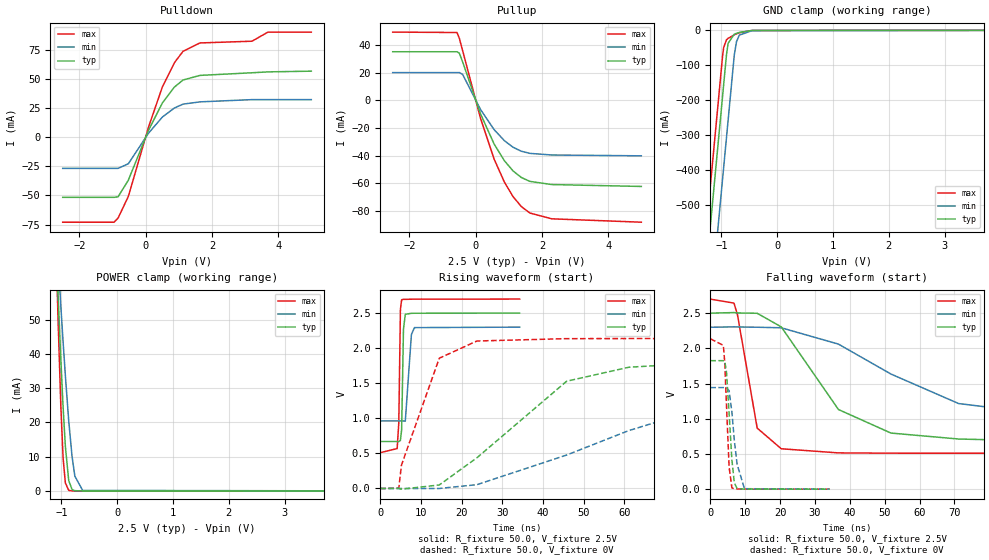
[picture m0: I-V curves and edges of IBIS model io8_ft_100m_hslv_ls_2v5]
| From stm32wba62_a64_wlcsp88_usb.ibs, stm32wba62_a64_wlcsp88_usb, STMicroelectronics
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[Model]   io8_ft_100m_hslv_ls_2v5
Model_type I/O
Polarity   Non-Inverting
Enable   Active-Low
| CAP_THRESHOLD on pad IOFT is "UDTCAPC" :
| Rising=30.0% of vddiom   Falling=70.0% of vddiom
| C_comp min and max val. don't necessarily correlate with the min and max pvt
| but are the smallest and greatest pad capacitance found.
| var   typ   min   max
C_comp   3.76303pF  3.70258pF  3.86851pF
|C_comp_pullup   2.23764pF  2.13239pF  2.37539pF
|C_comp_pulldown   1.52539pF  1.57019pF  1.49312pF
Vinl = 1.15V
Vinh = 1.35V
Vmeas = 1.25V   | Reference voltage for timing measurements
Cref  = 50.0pF   | Timing specification test load capacitance value
Rref  = 1.0MOhm   | Timing specification test load resistance value
Vref  = 1.375V   | Timing specification test load voltage
[Model Spec]
| TIME_THRESHOLD on pin ZIV11 is "CMOS" :
| Rising=50.0% of vdd   Falling=50.0% of vdd
Vinl 992.50000mV 921.50000mV 1.05850V
Vinh 1.43350V 1.32250V 1.51250V
| variable   typ   min   max
[Temperature Range] 25.0 140.0 -40.0
| variable   typ   min   max
[Voltage Range] 2.5V 2.3V 2.7V
| variable   typ   min   max
[POWER Clamp Reference] 2.5V 2.3V 2.7V
| variable   typ   min   max
[GND Clamp Reference] 0V 0V 0V
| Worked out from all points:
|   slope of the pulldown table from 0 to 0.375 V, typ, clamps not added: 16.2 ohm
|   slope of the pullup table from 0 to 0.375 V, typ, clamps not added: 16.7 ohm
|   GND clamp passes 1 mA (typ) near -0.51 V on its own axis
|   POWER clamp passes 1 mA (typ) near -0.83 V on its own axis
|   rising waveform, R_fixture 50.0, V_fixture 2.5V: 20-80 % time 285ps typ, 437ps min, 287ps max; typ from 0.67 V to 2.5 V
|   falling waveform, R_fixture 50.0, V_fixture 2.5V: 20-80 % time 15.8ns typ, 32.2ns min, 4.57ns max; typ from 2.5 V to 0.67 V
|   rising waveform, R_fixture 50.0, V_fixture 0V: 20-80 % time 21.6ns typ, 41.7ns min, 6.82ns max; typ from 0 V to 1.82 V
|   falling waveform, R_fixture 50.0, V_fixture 0V: 20-80 % time 1.29ns typ, 1.85ns min, 1.03ns max; typ from 1.82 V to 0 V
[POWER Clamp]
-2.5V     733.7mA    502.6mA    1.062A
-1.09V    69.42mA    75.17mA    67.14mA
-1.08V    65.31mA    72.42mA    61.23mA
-1.06V    57.23mA    66.98mA    49.77mA
-1.01V    38.06mA    53.68mA    24.29mA
-970mV    24.36mA    43.46mA    9.575mA
-930mV    13.06mA    33.74mA    2.352mA
-870mV    3.065mA    20.56mA    165.9uA
-810mV    418.4uA    10.06mA    10.3uA
-760mV    69.41uA    4.321mA    1.008uA
-620mV    424.8nA    151.9uA    1.655nA
5V        0A         0A         0A
[GND Clamp]
-2.5V     -2.774A    -3.011A    -2.658A
-1.45V    -988.6mA   -1.226A    -873.4mA
-1.21V    -580.6mA   -818.3mA   -465.4mA
-980mV    -189.6mA   -427.3mA   -74.41mA
-960mV    -155.6mA   -393.3mA   -49.14mA
-910mV    -70.61mA   -308.3mA   -27.43mA
-880mV    -37.05mA   -257.3mA   -22.95mA
-770mV    -11.2mA    -71.03mA   -13.02mA
-730mV    -8.651mA   -32.36mA   -10.11mA
-680mV    -6.129mA   -13.76mA   -6.945mA
-450mV    -356.3uA   -840.3uA   -213.1uA
5V        1.758nA    357.7nA    738.1pA
| variable   typ   min   max
[Pullup Reference] 2.5V 2.3V 2.7V
| variable   typ   min   max
[Pulldown Reference] 0V 0V 0V
[Pullup]
-2.5V     35.35mA    20.25mA    49.61mA
-560mV    35.35mA    20.25mA    49.3mA
-490mV    34.29mA    20.25mA    45.08mA
-390mV    27.95mA    18.88mA    36.11mA
150mV     -9.726mA   -6.535mA   -13.02mA
560mV     -31.59mA   -21.16mA   -42.52mA
870mV     -43.7mA    -29.15mA   -59.21mA
1.13V     -51.06mA   -33.88mA   -69.7mA
1.38V     -55.84mA   -36.8mA    -76.9mA
1.64V     -58.66mA   -38.35mA   -81.62mA
2.3V      -60.96mA   -39.52mA   -85.81mA
5V        -62.33mA   -40.13mA   -88.25mA
[Pulldown]
-2.5V     -51.61mA   -26.66mA   -73.01mA
-950mV    -51.61mA   -26.66mA   -73.01mA
-830mV    -51.13mA   -26.66mA   -69.5mA
-520mV    -36.86mA   -22.67mA   -50.81mA
90mV      6.214mA    3.696mA    8.997mA
510mV     29.86mA    17.62mA    43.74mA
870mV     43.36mA    25.34mA    64.34mA
1.13V     49.44mA    28.66mA    74.15mA
1.64V     53.42mA    30.62mA    81.36mA
3.21V     55.67mA    32.54mA    82.85mA
3.69V     56.44mA    32.54mA    90.68mA
5V        57.06mA    32.54mA    90.71mA
[Ramp]
dV/dt_r 1.09518V/21.22471ns 865.48725mV/41.50367ns 1.28201V/6.70344ns
dV/dt_f 1.09819V/15.37327ns 801.46434mV/31.97693ns 1.31366V/4.4126ns
R_load = 50.0
| Removed startup time: 0s 0s 0s  .
| Removed end time: 34.25ns.
[Rising Waveform]
R_fixture   = 50.0
V_fixture   = 2.5V
V_fixture_min = 2.3V
V_fixture_max = 2.7V
0s        669.7mV    963mV      510.6mV
4.15ns    669.7mV    963mV      569.2mV
4.55ns    668.8mV    963mV      935.7mV
4.95ns    684.4mV    963mV      2.551V
5.25ns    840mV      963mV      2.69V
5.7ns     2.273V     962.6mV    2.696V
6.15ns    2.483V     960.2mV    2.696V
7.65ns    2.497V     2.195V     2.698V
8.4ns     2.498V     2.293V     2.699V
34.25ns   2.5V       2.3V       2.7V
| Removed startup time: 0s 0s 0s  .
| Removed end time: 249.2ns.
[Falling Waveform]
R_fixture   = 50.0
V_fixture   = 2.5V
V_fixture_min = 2.3V
V_fixture_max = 2.7V
0s        2.5V       2.3V       2.7V
6.8ns     2.508V     2.305V     2.642V
7.8ns     2.503V     2.304V     2.476V
13.45ns   2.498V     2.3V       867.3mV
20.35ns   2.305V     2.292V     573.9mV
36.75ns   1.131V     2.06V      515.2mV
51.8ns    796.8mV    1.635V     511.1mV
71.2ns    712.3mV    1.216V     510.6mV
96.65ns   682.3mV    1.062V     510.6mV
249.2ns   669.7mV    964.2mV    510.6mV
| Removed startup time: 0s 0s 0s  .
| Removed end time: 249.25ns.
[Rising Waveform]
R_fixture   = 50.0
V_fixture   = 0V
V_fixture_min = 0V
V_fixture_max = 0V
0s        5.305nV    128.7nV    4.787nV
4.55ns    230.3uV    1.988uV    5.187mV
5.2ns     -9.662mV   14.49uV    332mV
14.5ns    50.22mV    348.4uV    1.857V
23.75ns   437.9mV    54.54mV    2.102V
45.8ns    1.529V     477mV      2.136V
61.05ns   1.728V     825.2mV    2.137V
81.4ns    1.797V     1.186V     2.137V
107.8ns   1.819V     1.355V     2.137V
249.3ns   1.825V     1.442V     2.137V
| Removed startup time: 0s 0s 0s  .
| Removed end time: 34.2ns.
[Falling Waveform]
R_fixture   = 50.0
V_fixture   = 0V
V_fixture_min = 0V
V_fixture_max = 0V
0s        1.825V     1.443V     2.137V
3.75ns    1.825V     1.443V     2.042V
4.15ns    1.819V     1.443V     1.8V
4.65ns    1.662V     1.443V     1.183V
5.4ns     1.072V     1.397V     313.7mV
6.2ns     414mV      1.094V     19.02mV
6.9ns     89.08mV    691.3mV    4.599mV
7.7ns     7.654mV    352.7mV    2.44mV
9.8ns     1.416mV    6.88mV     1.424mV
34.2ns    184.7uV    284.3uV    118.1uV
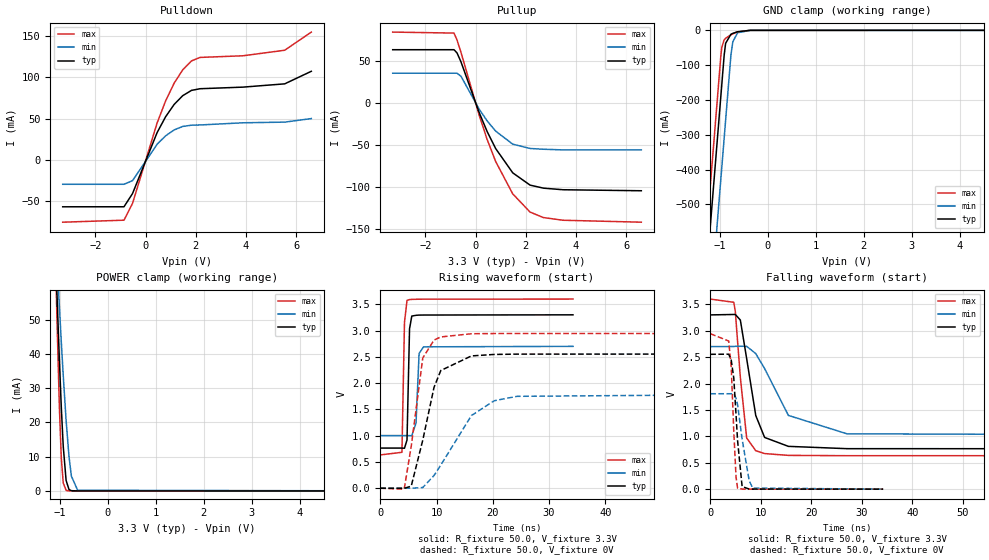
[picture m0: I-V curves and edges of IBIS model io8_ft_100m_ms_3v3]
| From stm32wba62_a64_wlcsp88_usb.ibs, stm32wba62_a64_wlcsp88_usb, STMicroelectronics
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[Model]   io8_ft_100m_ms_3v3
Model_type I/O
Polarity   Non-Inverting
Enable   Active-Low
| CAP_THRESHOLD on pad IOFT is "UDTCAPC" :
| Rising=30.0% of vddiom   Falling=70.0% of vddiom
| C_comp min and max val. don't necessarily correlate with the min and max pvt
| but are the smallest and greatest pad capacitance found.
| var   typ   min   max
C_comp   3.79769pF  3.69235pF  3.85115pF
|C_comp_pullup   2.35213pF  2.17427pF  2.43332pF
|C_comp_pulldown   1.44556pF  1.51808pF  1.41784pF
Vinl = 1.35V
Vinh = 1.8V
Vmeas = 1.65V   | Reference voltage for timing measurements
Cref  = 50.0pF   | Timing specification test load capacitance value
Rref  = 1.0MOhm   | Timing specification test load resistance value
Vref  = 1.815V   | Timing specification test load voltage
[Model Spec]
| TIME_THRESHOLD on pin ZIV11 is "CMOS" :
| Rising=50.0% of vdd   Falling=50.0% of vdd
Vinl 1.29050V 1.08050V 1.37650V
Vinh 1.79850V 1.52050V 1.90250V
| variable   typ   min   max
[Temperature Range] 25.0 140.0 -40.0
| variable   typ   min   max
[Voltage Range] 3.3V 2.7V 3.6V
| variable   typ   min   max
[POWER Clamp Reference] 3.3V 2.7V 3.6V
| variable   typ   min   max
[GND Clamp Reference] 0V 0V 0V
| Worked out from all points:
|   slope of the pulldown table from 0 to 0.495 V, typ, clamps not added: 14 ohm
|   slope of the pullup table from 0 to 0.495 V, typ, clamps not added: 13.8 ohm
|   GND clamp passes 1 mA (typ) near -0.51 V on its own axis
|   POWER clamp passes 1 mA (typ) near -0.83 V on its own axis
|   rising waveform, R_fixture 50.0, V_fixture 3.3V: 20-80 % time 257ps typ, 344ps min, 242ps max; typ from 0.764 V to 3.3 V
|   falling waveform, R_fixture 50.0, V_fixture 3.3V: 20-80 % time 2.84ns typ, 6.11ns min, 1.62ns max; typ from 3.3 V to 0.764 V
|   rising waveform, R_fixture 50.0, V_fixture 0V: 20-80 % time 3.16ns typ, 6.58ns min, 2.08ns max; typ from 0 V to 2.55 V
|   falling waveform, R_fixture 50.0, V_fixture 0V: 20-80 % time 1.01ns typ, 1.58ns min, 770ps max; typ from 2.55 V to 0 V
[POWER Clamp]
-3.3V     1.123A     753mA      1.645A
-1.09V    69.42mA    75.17mA    67.14mA
-1.08V    65.31mA    72.42mA    61.23mA
-1.06V    57.23mA    66.98mA    49.77mA
-1.01V    38.06mA    53.68mA    24.29mA
-970mV    24.36mA    43.46mA    9.575mA
-930mV    13.06mA    33.74mA    2.352mA
-870mV    3.065mA    20.56mA    165.9uA
-810mV    418.4uA    10.06mA    10.3uA
-760mV    69.41uA    4.321mA    1.009uA
-630mV    611.5nA    197uA      2.727nA
6.6V      0A         0A         0A
[GND Clamp]
-3.3V     -4.134A    -4.372A    -4.018A
-1.59V    -1.227A    -1.465A    -1.111A
-1.25V    -648.9mA   -886.9mA   -533mA
-980mV    -189.9mA   -427.9mA   -74mA
-960mV    -155.9mA   -393.9mA   -48.8mA
-910mV    -70.86mA   -308.9mA   -27.2mA
-880mV    -37.23mA   -257.9mA   -22.76mA
-770mV    -11.28mA   -71.59mA   -12.95mA
-730mV    -8.709mA   -32.74mA   -10.07mA
-630mV    -4.122mA   -6.943mA   -4.354mA
-370mV    -42.68uA   -212.2uA   -13.03uA
6.6V      2.311nA    506.4nA    1.057nA
| variable   typ   min   max
[Pullup Reference] 3.3V 2.7V 3.6V
| variable   typ   min   max
[Pulldown Reference] 0V 0V 0V
[Pullup]
-3.3V     63.23mA    35.34mA    84.14mA
-860mV    63.23mA    35.34mA    82.96mA
-740mV    59.49mA    35.34mA    74.87mA
-580mV    48.71mA    31.68mA    59.96mA
140mV     -11.11mA   -7.067mA   -14.16mA
460mV     -33.83mA   -21.24mA   -43.26mA
800mV     -54.04mA   -33.36mA   -69.41mA
1.48V     -82.86mA   -48.82mA   -107.8mA
2.17V     -97.42mA   -53.93mA   -129.4mA
2.7V      -101mA     -54.85mA   -135.9mA
3.48V     -102.9mA   -55.62mA   -139.1mA
6.6V      -104.1mA   -55.62mA   -141.4mA
[Pulldown]
-3.3V     -56.7mA    -29.42mA   -75.36mA
-860mV    -56.67mA   -29.42mA   -72.94mA
-520mV    -40.69mA   -25.01mA   -52.64mA
460mV     33.25mA    19.09mA    44.92mA
800mV     52.54mA    29.36mA    71.75mA
1.14V     67.41mA    36.49mA    93.2mA
1.48V     77.97mA    40.67mA    109.3mA
1.83V     84.38mA    42.18mA    120.1mA
2.17V     86.37mA    42.45mA    124.3mA
3.88V     88.31mA    45.1mA     126.3mA
5.54V     92.28mA    45.89mA    133mA
6.6V      107.5mA    50.2mA     155mA
[Ramp]
dV/dt_r 1.53258V/3.14502ns 1.08444V/6.42433ns 1.76673V/2.08391ns
dV/dt_f 1.52157V/2.56919ns 1.019V/5.67962ns 1.77971V/1.61656ns
R_load = 50.0
| Removed startup time: 0s 0s 0s  .
| Removed end time: 34.25ns.
[Rising Waveform]
R_fixture   = 50.0
V_fixture   = 3.3V
V_fixture_min = 2.7V
V_fixture_max = 3.6V
0s        764mV      1.002V     633.8mV
3.85ns    764.1mV    1.002V     683.7mV
4.3ns     761.2mV    1.002V     3.153V
4.75ns    917.8mV    1.002V     3.575V
5.2ns     3.033V     1.001V     3.59V
5.6ns     3.276V     999mV      3.594V
6.35ns    3.291V     1.237V     3.596V
6.9ns     3.295V     2.565V     3.597V
7.7ns     3.296V     2.691V     3.598V
34.25ns   3.3V       2.7V       3.6V
| Removed startup time: 0s 0s 0s  .
| Removed end time: 189.25ns.
[Falling Waveform]
R_fixture   = 50.0
V_fixture   = 3.3V
V_fixture_min = 2.7V
V_fixture_max = 3.6V
0s        3.3V       2.7V       3.6V
4.65ns    3.308V     2.701V     3.539V
4.95ns    3.308V     2.705V     3.365V
5.95ns    3.203V     2.706V     2.115V
7.2ns     2.471V     2.705V     969.3mV
9ns       1.394V     2.567V     727.8mV
10.75ns   979.4mV    2.284V     673.9mV
15.45ns   810.7mV    1.397V     639.7mV
27.05ns   766.9mV    1.048V     634mV
189.3ns   764mV      1.002V     633.8mV
| Removed startup time: 0s 0s 0s  .
| Removed end time: 99.2ns.
[Rising Waveform]
R_fixture   = 50.0
V_fixture   = 0V
V_fixture_min = 0V
V_fixture_max = 0V
0s        20.8nV     123.7nV    58.33nV
4.25ns    -1.312mV   3.786uV    -17.81mV
5.5ns     39.25mV    -134.8uV   797.2mV
7.55ns    914.9mV    13.42mV    2.478V
9.55ns    1.919V     241.9mV    2.82V
10.75ns   2.24V      440.3mV    2.879V
16.2ns    2.518V     1.384V     2.94V
20.25ns   2.546V     1.665V     2.944V
24.3ns    2.552V     1.749V     2.944V
99.2ns    2.554V     1.807V     2.945V
| Removed startup time: 0s 0s 0s  .
| Removed end time: 34.2ns.
[Falling Waveform]
R_fixture   = 50.0
V_fixture   = 0V
V_fixture_min = 0V
V_fixture_max = 0V
0s        2.554V     1.807V     2.945V
3.65ns    2.556V     1.807V     2.805V
4.15ns    2.442V     1.807V     2.307V
4.65ns    2.105V     1.812V     1.089V
5.1ns     1.404V     1.719V     227.3mV
5.4ns     918.9mV    1.602V     19.53mV
6.3ns     49.32mV    947mV      2.27mV
7.7ns     2.286mV    156.8mV    1.162mV
8.4ns     1.629mV    20.95mV    949.3uV
34.2ns    5.948uV    58.14uV    862.4nV
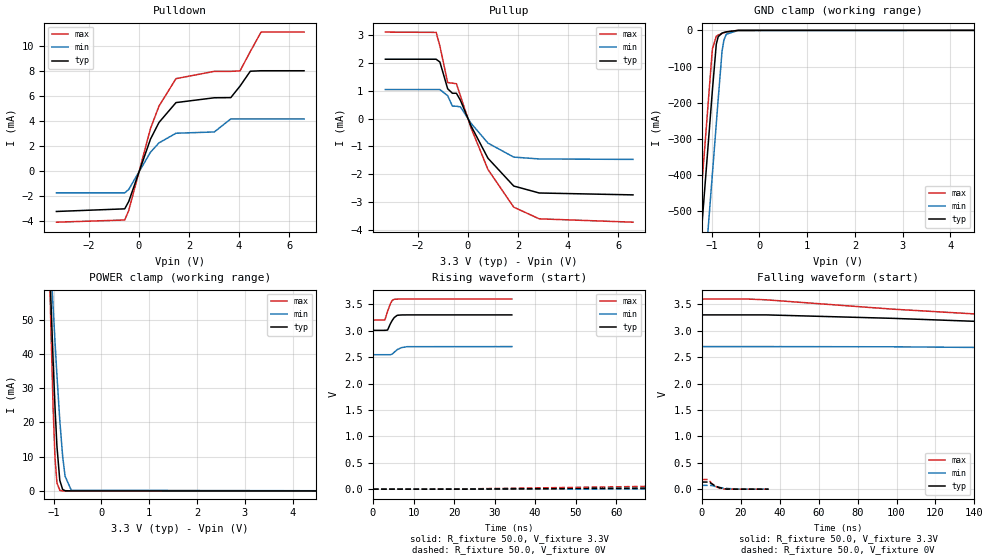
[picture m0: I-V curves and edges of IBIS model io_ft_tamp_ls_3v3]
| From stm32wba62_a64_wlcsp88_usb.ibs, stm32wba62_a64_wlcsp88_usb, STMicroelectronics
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[Model]   io_ft_tamp_ls_3v3
Model_type I/O
Polarity   Non-Inverting
Enable   Active-Low
| CAP_THRESHOLD on pad IOFT is "UDTCAPC" :
| Rising=30.0% of vddios   Falling=70.0% of vddios
| C_comp min and max val. don't necessarily correlate with the min and max pvt
| but are the smallest and greatest pad capacitance found.
| var   typ   min   max
C_comp   2.94466pF  2.88473pF  2.97349pF
|C_comp_pullup   1.80042pF  1.68790pF  1.84110pF
|C_comp_pulldown   1.14423pF  1.19683pF  1.13239pF
Vinl = 1.35V
Vinh = 1.8V
Vmeas = 1.65V   | Reference voltage for timing measurements
Cref  = 50.0pF   | Timing specification test load capacitance value
Rref  = 1.0MOhm   | Timing specification test load resistance value
Vref  = 1.815V   | Timing specification test load voltage
[Model Spec]
| TIME_THRESHOLD on pin ZIV11 is "CMOS" :
| Rising=50.0% of vdd   Falling=50.0% of vdd
Vinl 1.29050V 1.08050V 1.37650V
Vinh 1.79850V 1.52050V 1.90250V
| variable   typ   min   max
[Temperature Range] 25.0 140.0 -40.0
| variable   typ   min   max
[Voltage Range] 3.3V 2.7V 3.6V
| variable   typ   min   max
[POWER Clamp Reference] 3.3V 2.7V 3.6V
| variable   typ   min   max
[GND Clamp Reference] 0V 0V 0V
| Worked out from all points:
|   slope of the pulldown table from 0 to 0.495 V, typ, clamps not added: 186 ohm
|   slope of the pullup table from 0 to 0.495 V, typ, clamps not added: 523 ohm
|   GND clamp passes 1 mA (typ) near -0.54 V on its own axis
|   POWER clamp passes 1 mA (typ) near -0.83 V on its own axis
|   rising waveform, R_fixture 50.0, V_fixture 3.3V: 20-80 % time 1.21ns typ, 1.65ns min, 1.06ns max; typ from 3.01 V to 3.3 V
|   falling waveform, R_fixture 50.0, V_fixture 3.3V: 20-80 % time 142ns typ, 234ns min, 99.7ns max; typ from 3.3 V to 3.01 V
|   rising waveform, R_fixture 50.0, V_fixture 0V: 20-80 % time 166ns typ, 308ns min, 115ns max; typ from 0 V to 0.135 V
|   falling waveform, R_fixture 50.0, V_fixture 0V: 20-80 % time 4.46ns typ, 6.53ns min, 3.74ns max; typ from 0.135 V to 0 V
[POWER Clamp]
-3.3V     1.123A     753mA      1.645A
-1.09V    69.42mA    75.17mA    67.14mA
-1.08V    65.31mA    72.42mA    61.23mA
-1.06V    57.23mA    66.98mA    49.77mA
-1.01V    38.06mA    53.68mA    24.29mA
-970mV    24.36mA    43.46mA    9.575mA
-930mV    13.06mA    33.74mA    2.352mA
-870mV    3.065mA    20.56mA    165.9uA
-810mV    418.4uA    10.06mA    10.3uA
-760mV    69.41uA    4.321mA    1.008uA
-630mV    611nA      197uA      2.689nA
6.6V      0A         0A         0A
[GND Clamp]
-3.3V     -4.108A    -4.338A    -3.993A
-1.47V    -996.5mA   -1.227A    -882.1mA
-1.25V    -622.5mA   -853.4mA   -508.1mA
-990mV    -180.5mA   -411.4mA   -66.09mA
-980mV    -163.5mA   -394.4mA   -51.42mA
-900mV    -38.37mA   -258.4mA   -16.28mA
-860mV    -17.66mA   -190.4mA   -13.03mA
-780mV    -7.657mA   -58.45mA   -8.63mA
-740mV    -5.866mA   -26.35mA   -6.764mA
-690mV    -4.176mA   -10.78mA   -4.712mA
-450mV    -220.4uA   -529.3uA   -129.7uA
6.6V      1.984nA    498.7nA    735.2pA
| variable   typ   min   max
[Pullup Reference] 3.3V 2.7V 3.6V
| variable   typ   min   max
[Pulldown Reference] 0V 0V 0V
[Pullup]
-3.3V     2.139mA    1.048mA    3.116mA
-1.27V    2.139mA    1.048mA    3.106mA
-1.12V    2.038mA    1.048mA    2.612mA
-810mV    1.076mA    826.2uA    1.296mA
-620mV    914.6uA    451.9uA    1.28mA
-460mV    914.6uA    447.1uA    1.257mA
-300mV    660.2uA    425.1uA    820.6uA
120mV     -251.9uA   -160.4uA   -321uA
800mV     -1.423mA   -878.7uA   -1.828mA
1.83V     -2.424mA   -1.383mA   -3.184mA
2.85V     -2.675mA   -1.45mA    -3.605mA
6.6V      -2.743mA   -1.466mA   -3.726mA
[Pulldown]
-3.3V     -3.274mA   -1.782mA   -4.133mA
-570mV    -3.064mA   -1.782mA   -3.957mA
-410mV    -2.48mA    -1.511mA   -3.207mA
460mV     2.522mA    1.473mA    3.369mA
800mV     3.858mA    2.222mA    5.168mA
1.48V     5.45mA     2.995mA    7.37mA
3.01V     5.836mA    3.097mA    7.954mA
3.67V     5.848mA    4.142mA    7.954mA
4.04V     6.772mA    4.142mA    7.991mA
4.45V     7.963mA    4.142mA    9.539mA
4.88V     8.002mA    4.142mA    11.1mA
6.6V      8.002mA    4.142mA    11.1mA
[Ramp]
dV/dt_r 80.89923mV/165.45031ns 43.20406mV/308.11062ns 109.86367mV/114.45653ns
dV/dt_f 175.10448mV/141.49612ns 92.27507mV/233.79531ns 238.66494mV/99.51803ns
R_load = 50.0
| Removed startup time: 0s 0s 0s  .
| Removed end time: 34.25ns.
[Rising Waveform]
R_fixture   = 50.0
V_fixture   = 3.3V
V_fixture_min = 2.7V
V_fixture_max = 3.6V
0s        3.008V     2.546V     3.202V
2.95ns    3.008V     2.546V     3.205V
3.6ns     3.013V     2.546V     3.368V
4.3ns     3.134V     2.546V     3.512V
4.75ns    3.196V     2.558V     3.575V
5.25ns    3.251V     2.594V     3.596V
6ns       3.293V     2.643V     3.599V
7ns       3.299V     2.68V      3.6V
8.4ns     3.3V       2.698V     3.6V
34.25ns   3.3V       2.7V       3.6V
| Removed startup time: 0s 0s 0s  .
| Removed end time: 1.19925us.
[Falling Waveform]
R_fixture   = 50.0
V_fixture   = 3.3V
V_fixture_min = 2.7V
V_fixture_max = 3.6V
0s        3.3V       2.7V       3.6V
23.7ns    3.3V       2.7V       3.6V
33.3ns    3.3V       2.7V       3.585V
97.95ns   3.235V     2.696V     3.409V
158.6ns   3.154V     2.679V     3.279V
195.8ns   3.105V     2.666V     3.238V
244.8ns   3.059V     2.646V     3.216V
342.8ns   3.021V     2.602V     3.204V
538.5ns   3.009V     2.558V     3.202V
1.199us   3.008V     2.546V     3.202V
| Removed startup time: 0s 0s 0s  .
| Removed end time: 1.19925us.
[Rising Waveform]
R_fixture   = 50.0
V_fixture   = 0V
V_fixture_min = 0V
V_fixture_max = 0V
0s        79.54nV    353.3nV    261.5nV
22.2ns    186.6uV    -20.97uV   4.512mV
97.95ns   33.77mV    3.829mV    84.97mV
159.9ns   66.56mV    12.08mV    141mV
195.8ns   85.61mV    17.26mV    160.1mV
244.8ns   105.9mV    24.58mV    173.2mV
293.7ns   118.4mV    32.22mV    178.8mV
367.2ns   127.9mV    43.98mV    181.9mV
587.4ns   134.3mV    64.42mV    183.1mV
1.199us   134.8mV    72.01mV    183.1mV
| Removed startup time: 0s 0s 0s  .
| Removed end time: 34.25ns.
[Falling Waveform]
R_fixture   = 50.0
V_fixture   = 0V
V_fixture_min = 0V
V_fixture_max = 0V
0s        134.8mV    72.17mV    183.1mV
3.15ns    134.8mV    72.17mV    182.9mV
3.85ns    132.8mV    72.15mV    157.6mV
5.05ns    101.1mV    68.94mV    107.8mV
6.75ns    62.13mV    51.74mV    61.16mV
8.4ns     37.42mV    36.61mV    26.7mV
10.3ns    16.6mV     25.12mV    2.983mV
12.6ns    1.626mV    14.72mV    371uV
17.5ns    130.1uV    1.343mV    58.91uV
34.25ns   14.79uV    14.17uV    26.43uV
